One B-rep face of a CAD part: STEP entity #797.
In plain terms, the planar face has unit normal (0, 0, 1).
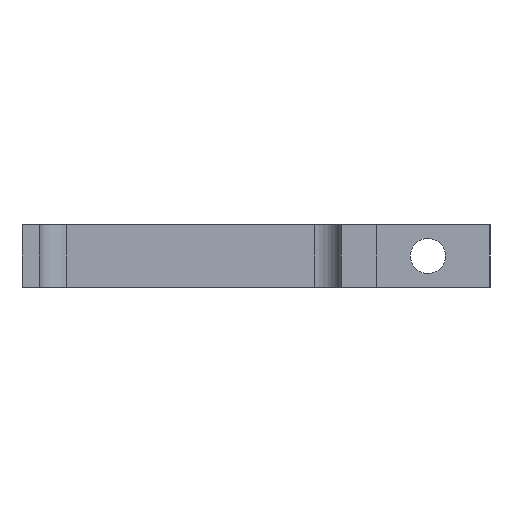
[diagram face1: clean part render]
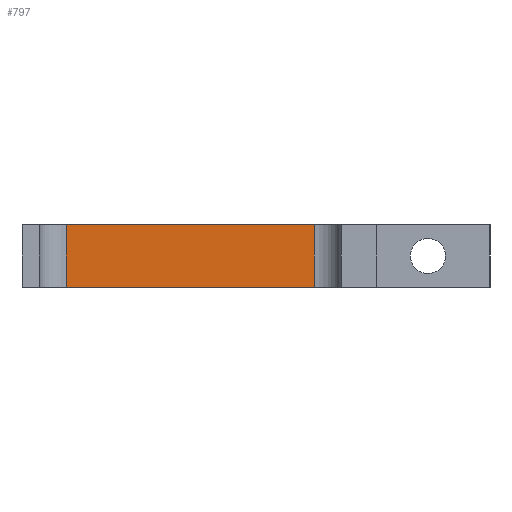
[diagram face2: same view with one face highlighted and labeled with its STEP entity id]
Its self-contained STEP definition (entity closure, numbers rounded to 3 decimals):
#50 = PLANE('',#51);
#51 = AXIS2_PLACEMENT_3D('',#52,#53,#54);
#52 = CARTESIAN_POINT('',(59.8,-46.959,4.8));
#53 = DIRECTION('',(1.,0.,0.));
#54 = DIRECTION('',(0.,0.,1.));
#216 = VERTEX_POINT('',#217);
#217 = CARTESIAN_POINT('',(59.8,-5.959,90.163));
#231 = PLANE('',#232);
#232 = AXIS2_PLACEMENT_3D('',#233,#234,#235);
#233 = CARTESIAN_POINT('',(59.8,-5.959,78.163));
#234 = DIRECTION('',(0.,1.,0.));
#235 = DIRECTION('',(0.,-0.,1.));
#243 = EDGE_CURVE('',#244,#216,#246,.T.);
#244 = VERTEX_POINT('',#245);
#245 = CARTESIAN_POINT('',(59.8,-29.959,90.163));
#246 = SURFACE_CURVE('',#247,(#251,#258),.PCURVE_S1.);
#247 = LINE('',#248,#249);
#248 = CARTESIAN_POINT('',(59.8,-29.959,90.163));
#249 = VECTOR('',#250,1.);
#250 = DIRECTION('',(0.,1.,0.));
#251 = PCURVE('',#50,#252);
#252 = DEFINITIONAL_REPRESENTATION('',(#253),#257);
#253 = LINE('',#254,#255);
#254 = CARTESIAN_POINT('',(85.363,-17.));
#255 = VECTOR('',#256,1.);
#256 = DIRECTION('',(0.,-1.));
#257 = ( GEOMETRIC_REPRESENTATION_CONTEXT(2) 
PARAMETRIC_REPRESENTATION_CONTEXT() REPRESENTATION_CONTEXT('2D SPACE',''
  ) );
#258 = PCURVE('',#259,#264);
#259 = PLANE('',#260);
#260 = AXIS2_PLACEMENT_3D('',#261,#262,#263);
#261 = CARTESIAN_POINT('',(59.8,-29.959,90.163));
#262 = DIRECTION('',(0.,0.,1.));
#263 = DIRECTION('',(1.,0.,-0.));
#264 = DEFINITIONAL_REPRESENTATION('',(#265),#269);
#265 = LINE('',#266,#267);
#266 = CARTESIAN_POINT('',(0.,0.));
#267 = VECTOR('',#268,1.);
#268 = DIRECTION('',(0.,1.));
#269 = ( GEOMETRIC_REPRESENTATION_CONTEXT(2) 
PARAMETRIC_REPRESENTATION_CONTEXT() REPRESENTATION_CONTEXT('2D SPACE',''
  ) );
#287 = PLANE('',#288);
#288 = AXIS2_PLACEMENT_3D('',#289,#290,#291);
#289 = CARTESIAN_POINT('',(59.8,-29.959,78.163));
#290 = DIRECTION('',(0.,1.,0.));
#291 = DIRECTION('',(0.,-0.,1.));
#539 = PLANE('',#540);
#540 = AXIS2_PLACEMENT_3D('',#541,#542,#543);
#541 = CARTESIAN_POINT('',(65.8,-46.959,4.8));
#542 = DIRECTION('',(1.,0.,0.));
#543 = DIRECTION('',(0.,0.,1.));
#753 = VERTEX_POINT('',#754);
#754 = CARTESIAN_POINT('',(65.8,-29.959,90.163));
#777 = EDGE_CURVE('',#244,#753,#778,.T.);
#778 = SURFACE_CURVE('',#779,(#783,#790),.PCURVE_S1.);
#779 = LINE('',#780,#781);
#780 = CARTESIAN_POINT('',(59.8,-29.959,90.163));
#781 = VECTOR('',#782,1.);
#782 = DIRECTION('',(1.,0.,0.));
#783 = PCURVE('',#287,#784);
#784 = DEFINITIONAL_REPRESENTATION('',(#785),#789);
#785 = LINE('',#786,#787);
#786 = CARTESIAN_POINT('',(12.,0.));
#787 = VECTOR('',#788,1.);
#788 = DIRECTION('',(0.,1.));
#789 = ( GEOMETRIC_REPRESENTATION_CONTEXT(2) 
PARAMETRIC_REPRESENTATION_CONTEXT() REPRESENTATION_CONTEXT('2D SPACE',''
  ) );
#790 = PCURVE('',#259,#791);
#791 = DEFINITIONAL_REPRESENTATION('',(#792),#796);
#792 = LINE('',#793,#794);
#793 = CARTESIAN_POINT('',(0.,0.));
#794 = VECTOR('',#795,1.);
#795 = DIRECTION('',(1.,0.));
#796 = ( GEOMETRIC_REPRESENTATION_CONTEXT(2) 
PARAMETRIC_REPRESENTATION_CONTEXT() REPRESENTATION_CONTEXT('2D SPACE',''
  ) );
#797 = ADVANCED_FACE('',(#798),#259,.T.);
#798 = FACE_BOUND('',#799,.T.);
#799 = EDGE_LOOP('',(#800,#801,#802,#825));
#800 = ORIENTED_EDGE('',*,*,#243,.F.);
#801 = ORIENTED_EDGE('',*,*,#777,.T.);
#802 = ORIENTED_EDGE('',*,*,#803,.T.);
#803 = EDGE_CURVE('',#753,#804,#806,.T.);
#804 = VERTEX_POINT('',#805);
#805 = CARTESIAN_POINT('',(65.8,-5.959,90.163));
#806 = SURFACE_CURVE('',#807,(#811,#818),.PCURVE_S1.);
#807 = LINE('',#808,#809);
#808 = CARTESIAN_POINT('',(65.8,-29.959,90.163));
#809 = VECTOR('',#810,1.);
#810 = DIRECTION('',(0.,1.,0.));
#811 = PCURVE('',#259,#812);
#812 = DEFINITIONAL_REPRESENTATION('',(#813),#817);
#813 = LINE('',#814,#815);
#814 = CARTESIAN_POINT('',(6.,0.));
#815 = VECTOR('',#816,1.);
#816 = DIRECTION('',(0.,1.));
#817 = ( GEOMETRIC_REPRESENTATION_CONTEXT(2) 
PARAMETRIC_REPRESENTATION_CONTEXT() REPRESENTATION_CONTEXT('2D SPACE',''
  ) );
#818 = PCURVE('',#539,#819);
#819 = DEFINITIONAL_REPRESENTATION('',(#820),#824);
#820 = LINE('',#821,#822);
#821 = CARTESIAN_POINT('',(85.363,-17.));
#822 = VECTOR('',#823,1.);
#823 = DIRECTION('',(0.,-1.));
#824 = ( GEOMETRIC_REPRESENTATION_CONTEXT(2) 
PARAMETRIC_REPRESENTATION_CONTEXT() REPRESENTATION_CONTEXT('2D SPACE',''
  ) );
#825 = ORIENTED_EDGE('',*,*,#826,.F.);
#826 = EDGE_CURVE('',#216,#804,#827,.T.);
#827 = SURFACE_CURVE('',#828,(#832,#839),.PCURVE_S1.);
#828 = LINE('',#829,#830);
#829 = CARTESIAN_POINT('',(59.8,-5.959,90.163));
#830 = VECTOR('',#831,1.);
#831 = DIRECTION('',(1.,0.,0.));
#832 = PCURVE('',#259,#833);
#833 = DEFINITIONAL_REPRESENTATION('',(#834),#838);
#834 = LINE('',#835,#836);
#835 = CARTESIAN_POINT('',(0.,24.));
#836 = VECTOR('',#837,1.);
#837 = DIRECTION('',(1.,0.));
#838 = ( GEOMETRIC_REPRESENTATION_CONTEXT(2) 
PARAMETRIC_REPRESENTATION_CONTEXT() REPRESENTATION_CONTEXT('2D SPACE',''
  ) );
#839 = PCURVE('',#231,#840);
#840 = DEFINITIONAL_REPRESENTATION('',(#841),#845);
#841 = LINE('',#842,#843);
#842 = CARTESIAN_POINT('',(12.,0.));
#843 = VECTOR('',#844,1.);
#844 = DIRECTION('',(0.,1.));
#845 = ( GEOMETRIC_REPRESENTATION_CONTEXT(2) 
PARAMETRIC_REPRESENTATION_CONTEXT() REPRESENTATION_CONTEXT('2D SPACE',''
  ) );
